One B-rep face of a CAD part: STEP entity #154355.
In plain terms, the planar face has unit normal (0.99, -0.143, 0).
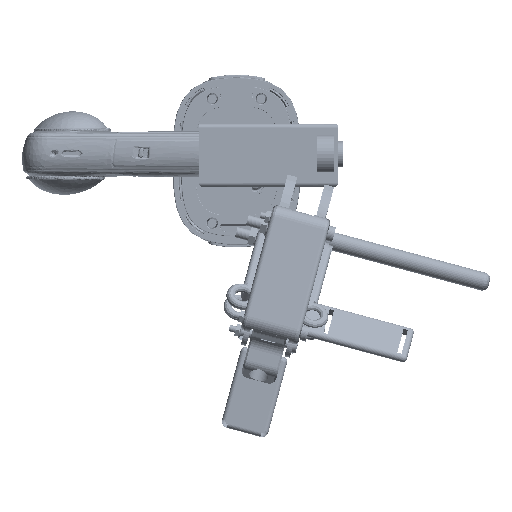
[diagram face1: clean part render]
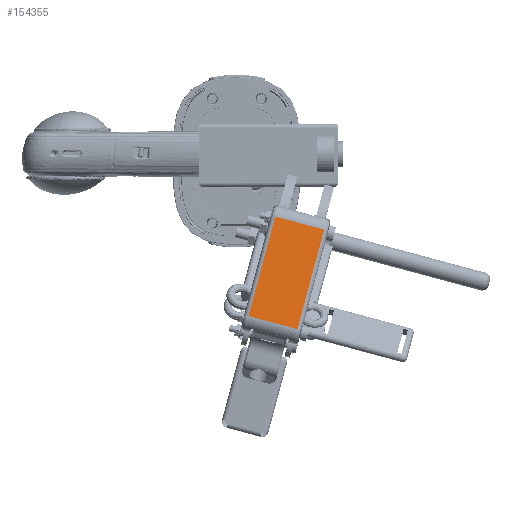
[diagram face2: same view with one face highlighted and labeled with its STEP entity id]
Its self-contained STEP definition (entity closure, numbers rounded to 3 decimals):
#152991 = CYLINDRICAL_SURFACE('',#152992,2.);
#152992 = AXIS2_PLACEMENT_3D('',#152993,#152994,#152995);
#152993 = CARTESIAN_POINT('',(75.243,96.478,
    11.6));
#152994 = DIRECTION('',(-0.143,-0.99,
    0.));
#152995 = DIRECTION('',(0.99,-0.143,0.
    ));
#154144 = CYLINDRICAL_SURFACE('',#154145,6.);
#154145 = AXIS2_PLACEMENT_3D('',#154146,#154147,#154148);
#154146 = CARTESIAN_POINT('',(64.5,50.015,
    13.6));
#154147 = DIRECTION('',(0.,0.,-1.));
#154148 = DIRECTION('',(-1.,0.,0.));
#154274 = VERTEX_POINT('',#154275);
#154275 = CARTESIAN_POINT('',(70.439,49.159,
    -11.6));
#154306 = EDGE_CURVE('',#154274,#154307,#154309,.T.);
#154307 = VERTEX_POINT('',#154308);
#154308 = CARTESIAN_POINT('',(70.439,49.159,
    11.6));
#154309 = SURFACE_CURVE('',#154310,(#154314,#154321),.PCURVE_S1.);
#154310 = LINE('',#154311,#154312);
#154311 = CARTESIAN_POINT('',(70.439,49.159,
    13.6));
#154312 = VECTOR('',#154313,1.);
#154313 = DIRECTION('',(0.,0.,1.));
#154314 = PCURVE('',#154144,#154315);
#154315 = DEFINITIONAL_REPRESENTATION('',(#154316),#154320);
#154316 = LINE('',#154317,#154318);
#154317 = CARTESIAN_POINT('',(3.285,0.));
#154318 = VECTOR('',#154319,1.);
#154319 = DIRECTION('',(0.,-1.));
#154320 = ( GEOMETRIC_REPRESENTATION_CONTEXT(2) 
PARAMETRIC_REPRESENTATION_CONTEXT() REPRESENTATION_CONTEXT('2D SPACE',''
  ) );
#154321 = PCURVE('',#154322,#154327);
#154322 = PLANE('',#154323);
#154323 = AXIS2_PLACEMENT_3D('',#154324,#154325,#154326);
#154324 = CARTESIAN_POINT('',(70.439,49.159,
    13.6));
#154325 = DIRECTION('',(-0.99,0.143,0.)
  );
#154326 = DIRECTION('',(-0.143,-0.99,
    0.));
#154327 = DEFINITIONAL_REPRESENTATION('',(#154328),#154332);
#154328 = LINE('',#154329,#154330);
#154329 = CARTESIAN_POINT('',(-0.,0.));
#154330 = VECTOR('',#154331,1.);
#154331 = DIRECTION('',(0.,1.));
#154332 = ( GEOMETRIC_REPRESENTATION_CONTEXT(2) 
PARAMETRIC_REPRESENTATION_CONTEXT() REPRESENTATION_CONTEXT('2D SPACE',''
  ) );
#154355 = ADVANCED_FACE('',(#154356),#154322,.F.);
#154356 = FACE_BOUND('',#154357,.T.);
#154357 = EDGE_LOOP('',(#154358,#154386,#154414,#154435));
#154358 = ORIENTED_EDGE('',*,*,#154359,.F.);
#154359 = EDGE_CURVE('',#154360,#154274,#154362,.T.);
#154360 = VERTEX_POINT('',#154361);
#154361 = CARTESIAN_POINT('',(77.222,96.192,
    -11.6));
#154362 = SURFACE_CURVE('',#154363,(#154367,#154374),.PCURVE_S1.);
#154363 = LINE('',#154364,#154365);
#154364 = CARTESIAN_POINT('',(70.439,49.159,
    -11.6));
#154365 = VECTOR('',#154366,1.);
#154366 = DIRECTION('',(-0.143,-0.99,
    0.));
#154367 = PCURVE('',#154322,#154368);
#154368 = DEFINITIONAL_REPRESENTATION('',(#154369),#154373);
#154369 = LINE('',#154370,#154371);
#154370 = CARTESIAN_POINT('',(0.,-25.2));
#154371 = VECTOR('',#154372,1.);
#154372 = DIRECTION('',(1.,0.));
#154373 = ( GEOMETRIC_REPRESENTATION_CONTEXT(2) 
PARAMETRIC_REPRESENTATION_CONTEXT() REPRESENTATION_CONTEXT('2D SPACE',''
  ) );
#154374 = PCURVE('',#154375,#154380);
#154375 = CYLINDRICAL_SURFACE('',#154376,2.);
#154376 = AXIS2_PLACEMENT_3D('',#154377,#154378,#154379);
#154377 = CARTESIAN_POINT('',(68.459,49.444,
    -11.6));
#154378 = DIRECTION('',(0.143,0.99,0.)
  );
#154379 = DIRECTION('',(-0.99,0.143,0.)
  );
#154380 = DEFINITIONAL_REPRESENTATION('',(#154381),#154385);
#154381 = LINE('',#154382,#154383);
#154382 = CARTESIAN_POINT('',(3.142,0.));
#154383 = VECTOR('',#154384,1.);
#154384 = DIRECTION('',(0.,-1.));
#154385 = ( GEOMETRIC_REPRESENTATION_CONTEXT(2) 
PARAMETRIC_REPRESENTATION_CONTEXT() REPRESENTATION_CONTEXT('2D SPACE',''
  ) );
#154386 = ORIENTED_EDGE('',*,*,#154387,.T.);
#154387 = EDGE_CURVE('',#154360,#154388,#154390,.T.);
#154388 = VERTEX_POINT('',#154389);
#154389 = CARTESIAN_POINT('',(77.222,96.192,
    11.6));
#154390 = SURFACE_CURVE('',#154391,(#154395,#154402),.PCURVE_S1.);
#154391 = LINE('',#154392,#154393);
#154392 = CARTESIAN_POINT('',(77.222,96.192,
    13.6));
#154393 = VECTOR('',#154394,1.);
#154394 = DIRECTION('',(0.,0.,1.));
#154395 = PCURVE('',#154322,#154396);
#154396 = DEFINITIONAL_REPRESENTATION('',(#154397),#154401);
#154397 = LINE('',#154398,#154399);
#154398 = CARTESIAN_POINT('',(-47.52,0.));
#154399 = VECTOR('',#154400,1.);
#154400 = DIRECTION('',(0.,1.));
#154401 = ( GEOMETRIC_REPRESENTATION_CONTEXT(2) 
PARAMETRIC_REPRESENTATION_CONTEXT() REPRESENTATION_CONTEXT('2D SPACE',''
  ) );
#154402 = PCURVE('',#154403,#154408);
#154403 = CYLINDRICAL_SURFACE('',#154404,6.);
#154404 = AXIS2_PLACEMENT_3D('',#154405,#154406,#154407);
#154405 = CARTESIAN_POINT('',(71.284,97.049,
    13.6));
#154406 = DIRECTION('',(0.,0.,-1.));
#154407 = DIRECTION('',(-1.,0.,0.));
#154408 = DEFINITIONAL_REPRESENTATION('',(#154409),#154413);
#154409 = LINE('',#154410,#154411);
#154410 = CARTESIAN_POINT('',(3.285,0.));
#154411 = VECTOR('',#154412,1.);
#154412 = DIRECTION('',(0.,-1.));
#154413 = ( GEOMETRIC_REPRESENTATION_CONTEXT(2) 
PARAMETRIC_REPRESENTATION_CONTEXT() REPRESENTATION_CONTEXT('2D SPACE',''
  ) );
#154414 = ORIENTED_EDGE('',*,*,#154415,.T.);
#154415 = EDGE_CURVE('',#154388,#154307,#154416,.T.);
#154416 = SURFACE_CURVE('',#154417,(#154421,#154428),.PCURVE_S1.);
#154417 = LINE('',#154418,#154419);
#154418 = CARTESIAN_POINT('',(70.439,49.159,
    11.6));
#154419 = VECTOR('',#154420,1.);
#154420 = DIRECTION('',(-0.143,-0.99,
    0.));
#154421 = PCURVE('',#154322,#154422);
#154422 = DEFINITIONAL_REPRESENTATION('',(#154423),#154427);
#154423 = LINE('',#154424,#154425);
#154424 = CARTESIAN_POINT('',(0.,-2.));
#154425 = VECTOR('',#154426,1.);
#154426 = DIRECTION('',(1.,0.));
#154427 = ( GEOMETRIC_REPRESENTATION_CONTEXT(2) 
PARAMETRIC_REPRESENTATION_CONTEXT() REPRESENTATION_CONTEXT('2D SPACE',''
  ) );
#154428 = PCURVE('',#152991,#154429);
#154429 = DEFINITIONAL_REPRESENTATION('',(#154430),#154434);
#154430 = LINE('',#154431,#154432);
#154431 = CARTESIAN_POINT('',(0.,47.52));
#154432 = VECTOR('',#154433,1.);
#154433 = DIRECTION('',(0.,1.));
#154434 = ( GEOMETRIC_REPRESENTATION_CONTEXT(2) 
PARAMETRIC_REPRESENTATION_CONTEXT() REPRESENTATION_CONTEXT('2D SPACE',''
  ) );
#154435 = ORIENTED_EDGE('',*,*,#154306,.F.);
